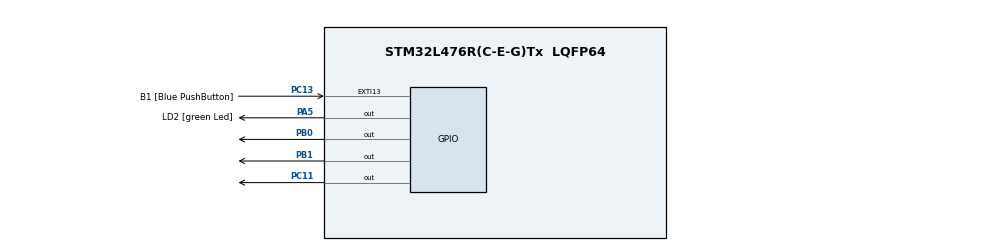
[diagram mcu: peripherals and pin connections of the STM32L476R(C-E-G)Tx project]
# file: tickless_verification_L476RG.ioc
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Mcu.Family=STM32L4
Mcu.Name=STM32L476R(C-E-G)Tx
Mcu.Package=LQFP64
NVIC.PriorityGroup=NVIC_PRIORITYGROUP_4
PA13\ (JTMS-SWDIO).GPIO_Label=TMS
PA13\ (JTMS-SWDIO).Signal=SYS_JTMS-SWDIO
PA14\ (JTCK-SWCLK).GPIO_Label=TCK
PA14\ (JTCK-SWCLK).Signal=SYS_JTCK-SWCLK
PA2.GPIO_Label=USART_TX
PA2.GPIO_Mode=GPIO_MODE_AF_PP
PA2.GPIO_PuPd=GPIO_NOPULL
PA2.GPIO_Speed=GPIO_SPEED_FREQ_VERY_HIGH
PA2.Signal=USART2_TX
PA3.GPIO_Label=USART_RX
PA3.GPIO_Mode=GPIO_MODE_AF_PP
PA3.GPIO_PuPd=GPIO_NOPULL
PA3.GPIO_Speed=GPIO_SPEED_FREQ_VERY_HIGH
PA3.Signal=USART2_RX
PA5.GPIO_Label=LD2 [green Led]
PA5.GPIO_ModeDefaultOutputPP=GPIO_MODE_OUTPUT_PP
PA5.GPIO_PuPd=GPIO_NOPULL
PA5.GPIO_Speed=GPIO_SPEED_FREQ_LOW
PA5.Signal=GPIO_Output
PB0.Signal=GPIO_Output
PB1.Signal=GPIO_Output
PB3\ (JTDO-TRACESWO).GPIO_Label=SWO
PB3\ (JTDO-TRACESWO).Signal=SYS_JTDO-SWO
PC11.Signal=GPIO_Output
PC13.GPIO_Label=B1 [Blue PushButton]
PC13.GPIO_ModeDefaultEXTI=GPIO_MODE_IT_FALLING
PC13.GPIO_PuPd=GPIO_NOPULL
PC13.Signal=GPXTI13
PC14-OSC32_IN\ (PC14).Signal=RCC_OSC32_IN
PC15-OSC32_OUT\ (PC15).Signal=RCC_OSC32_OUT
PH0-OSC_IN\ (PH0).Signal=RCC_OSC_IN
PH1-OSC_OUT\ (PH1).Signal=RCC_OSC_OUT
ProjectManager.HeapSize=0x200
ProjectManager.StackSize=0x400
ProjectManager.TargetToolchain=MDK-ARM V5
RCC.ADCFreq_Value=64000000
RCC.AHBFreq_Value=80000000
RCC.APB1Freq_Value=80000000
RCC.APB1TimFreq_Value=80000000
RCC.APB2Freq_Value=80000000
RCC.APB2TimFreq_Value=80000000
RCC.CortexFreq_Value=80000000
RCC.HCLKFreq_Value=80000000
RCC.HSE_VALUE=8000000
RCC.HSI_VALUE=16000000
RCC.LSE_VALUE=32768
RCC.MSI_VALUE=4000000
RCC.PLLN=10
RCC.PLLSourceVirtual=RCC_PLLSOURCE_HSI
RCC.PREFETCH_ENABLE=1
RCC.SYSCLKFreq_VALUE=80000000
RCC.SYSCLKSource=RCC_SYSCLKSOURCE_PLLCLK
RCC.USBFreq_Value=64000000
RCC.VCOOutputFreq_Value=160000000
board=NUCLEO-L476RG

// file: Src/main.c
/* USER CODE BEGIN Header */
/**
  ******************************************************************************
  * @file           : main.c
  * @brief          : Main program body
  ******************************************************************************
  * @attention
  *
  * <h2><center>&copy; Copyright (c) 2020 STMicroelectronics.
  * All rights reserved.</center></h2>
  *
  * This software component is licensed by ST under BSD 3-Clause license,
  * the "License"; You may not use this file except in compliance with the
  * License. You may obtain a copy of the License at:
  *                        opensource.org/licenses/BSD-3-Clause
  *
  ******************************************************************************
  */
/* USER CODE END Header */

#include "main.h"

void SystemClock_Config(void);
void tickless_testapp(void);
static void detect_debugger(void);

int main(void)
{

  /* MCU Configuration--------------------------------------------------------*/

  /* Reset of all peripherals, Initializes the Flash interface and the Systick. */
  HAL_Init();

  /* Configure the system clock */
  SystemClock_Config();

  /* USER CODE BEGIN SysInit */

  /* Turn off the Systick timer. */
  SysTick->CTRL = 0;

  detect_debugger();

  tickless_testapp();
  /* USER CODE END SysInit */

  /* Initialize all configured peripherals */

  /* Infinite loop */
  while (1)
  {

  }
}

void SystemClock_Config(void)
{
  RCC_OscInitTypeDef RCC_OscInitStruct = {0};
  RCC_ClkInitTypeDef RCC_ClkInitStruct = {0};
  RCC_PeriphCLKInitTypeDef PeriphClkInitStruct = {0};

  /** Initializes the CPU, AHB and APB busses clocks
  */
  RCC_OscInitStruct.OscillatorType = RCC_OSCILLATORTYPE_HSI | RCC_OSCILLATORTYPE_LSE;
  RCC_OscInitStruct.HSIState = RCC_HSI_ON;
  RCC_OscInitStruct.HSICalibrationValue = RCC_HSICALIBRATION_DEFAULT;
  RCC_OscInitStruct.LSEState = RCC_LSE_ON;
  RCC_OscInitStruct.PLL.PLLState = RCC_PLL_NONE;
  if (HAL_RCC_OscConfig(&RCC_OscInitStruct) != HAL_OK)
  {
    Error_Handler();
  }
  /** Initializes the CPU, AHB and APB busses clocks
  */
  RCC_ClkInitStruct.ClockType = RCC_CLOCKTYPE_HCLK|RCC_CLOCKTYPE_SYSCLK
                              |RCC_CLOCKTYPE_PCLK1|RCC_CLOCKTYPE_PCLK2;
  RCC_ClkInitStruct.SYSCLKSource = RCC_SYSCLKSOURCE_HSI;
  RCC_ClkInitStruct.AHBCLKDivider = RCC_SYSCLK_DIV1;
  RCC_ClkInitStruct.APB1CLKDivider = RCC_HCLK_DIV1;
  RCC_ClkInitStruct.APB2CLKDivider = RCC_HCLK_DIV1;

  if (HAL_RCC_ClockConfig(&RCC_ClkInitStruct, FLASH_LATENCY_4) != HAL_OK)
  {
    Error_Handler();
  }
  /** Initializes the peripherals clocks
  */
  PeriphClkInitStruct.PeriphClockSelection = RCC_PERIPHCLK_LPTIM2;
  PeriphClkInitStruct.Lptim2ClockSelection = RCC_LPTIM2CLKSOURCE_LSE;

  if (HAL_RCCEx_PeriphCLKConfig(&PeriphClkInitStruct) != HAL_OK)
  {
    Error_Handler();
  }

  /** Configure the main internal regulator output voltage
  */
  if (HAL_PWREx_ControlVoltageScaling(PWR_REGULATOR_VOLTAGE_SCALE1) != HAL_OK)
  {
    Error_Handler();
  }
}

/* USER CODE BEGIN 4 */

static void detect_debugger(void)
{
    // Check ARM DHCSR register. Bit cleared when debugger is NOT in use
    if((CoreDebug->DHCSR & 0x0001) == 0)
    {
        // Reset DBG_STOP in the DBGMCU CR register to 0. Debugger NOT in use
        DBGMCU->CR &= ~(DBGMCU_CR_DBG_STOP);
    }
    else
    {
        // Set DBG_STOP in the DBGMCU CR register to 1. Debugger in use
        DBGMCU->CR |= DBGMCU_CR_DBG_STOP;
    }
}

/* USER CODE END 4 */

void Error_Handler(void)
{
}

/************************ (C) COPYRIGHT STMicroelectronics *****END OF FILE****/
